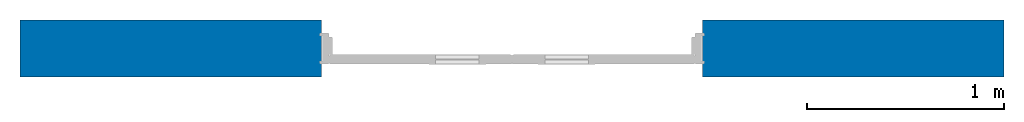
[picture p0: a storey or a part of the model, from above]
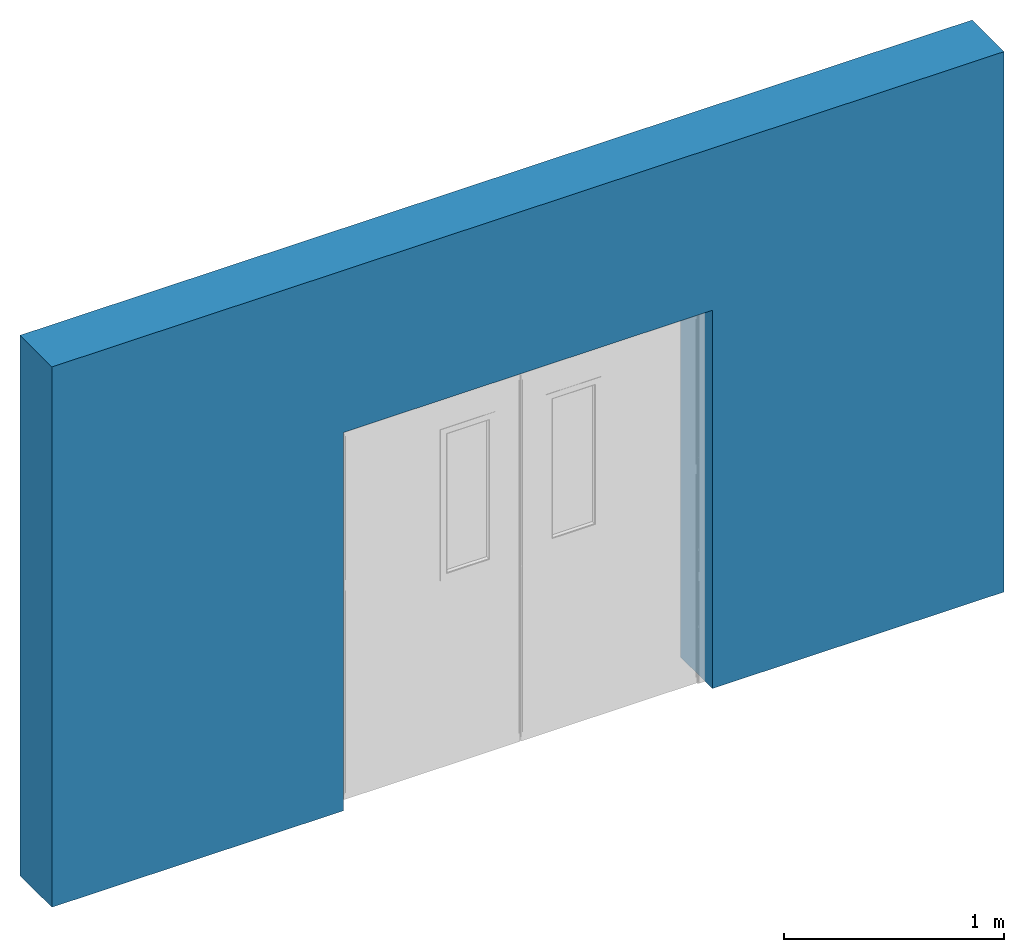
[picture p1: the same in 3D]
Properties of the parts of a building model (IFC2X3)

# File
Description: ViewDefinition [CoordinationView_V2.0]
File name: Project Number
Time: 2016-07-19T09:51:49
Written by: The EXPRESS Data Manager Version 5.01.0100.02.64mod : 6 Jun 2012
Made in: 20131024_2115(x64) - Exporter 3.13.0.0 - Alternate UI 2.13.0.0
Comment: STEP Physical File produced by: The EXPRESS Data Manager Version 5.01.0100.02.64mod : 6 Jun 2012* Module: EDMstepFileFactory/EDMstandAlone* Creation date: Tue Jul 19 09:51:49 2016* Host: ncl-PI11* Database: C:\Users\batyg\AppData\Local\Temp\{1545D58F-4297-423B-B04A-D624175F126E}\ifc* Database version: 5507* Database creation date: Tue Jul 19 09:51:48 2016* Schema: IFC2X3* Model: DataRepository.ifc* Model creation date: Tue Jul 19 09:51:48 2016* Header model: DataRepository.ifc_HeaderModel* Header model creation date: Tue Jul 19 09:51:48 2016* EDMuser: sdai-user* EDMgroup: sdai-group* License ID and type: 5605 : Permanent license. Expiry date: * EDMstepFileFactory options: 020000

# IfcProject, Project Number
LongName: Project Name; Phase: Project Status

# IfcSite, Default
RefLatitude: 51, 30, 0, 549316; RefLongitude: 0, -7, -34, -450321; RefElevation: 0 mm

# IfcBuildingStorey, Level 0
LongName: Level 0; Elevation: 0 mm

# IfcDoor: PostformedDoubleDoorset-VisionPanel11_3Piece_1936x2100mm, NBS_SDSProtectionLtd_CompDrsts_PostformedDoubleDoorset-VisionPanel11:PostformedDoubleDoorset-VisionPanel11_3Piece_1936x2100mm:221256
In: Level 0
Type - OperationType: DOUBLE_DOOR_SINGLE_SWING; ConstructionType: WOOD; ParameterTakesPrecedence: no; Sizeable: no; Material: NBS_Glass_Single, NBS_Concept
Type - NBS_SDSProtectionLtd_CompDrsts_PostformedDoubleDoorset-VisionPanel11:PostformedDoubleDoorset-VisionPanel11_3Piece_1936x2100mm:221256 - PanelOperation: SWINGING
Type - NBS_General - Author: NBS; BIMObjectName: NBS_SDSProtectionLtd_CompositeDoorsets_PostformedDoubleDoorset-VisionPanel11; ManufacturerName: SDS Protection Ltd; ManufacturerURL: www.sdsprotection.co.uk; NBSCertification: http://www.nationalbimlibrary.com/cert/n01kh5x3; NBSDescription: Composite doorsets; NBSNote: n/a; NBSOfficeMasterTag: n/a; NBSReference: 45-25-28/342; NBSTypeID: n/a; ProductInformation: www.sdsprotection.co.uk/doorsets/plastic-encapsulated; Revision: n/a; Uniclass2: 45-60-03/417; Uniclass2015Description: Composite doorsets; Uniclass2015Reference: Pr_30_59_24_16; Uniclass2015Version: Products v1.1; Version: 2
Type - NBS_Data - Accessories: n/a; AcousticPerformanceOptions: Non acoustic rated, 30 dB, 32 dB, 35 dB, 40 dB, 41 dB; AirTransferGrille: no; AirTransferGrilleSize: n/a; AntiFingerTrapRequirement: no; ArchitravesFinishAndColour: n/a; ArchitravesMaterial: n/a; ArchitravesWoodAppearanceClass: n/a; Configuration: Single leaf, single action; DoorFrameColourOptions: Many options available, consult manufacturer's literature; DoorFrameFinishOptions: Fully encapsulated - dFend, Fully encapsulated - Durablend, Fully encapsulated - Hydroclean, Fully encapsulated - Woodgrain, Lacquered, Pre-primed; DoorFrameTypeOptions: Rebated, Split-frame, Traditional; DoorLeafBeadingFixing: n/a; DoorLeafBeadingMaterial: n/a; DoorLeafBeadingType: n/a; DoorLeafCoreOptions: Block, Particle; DoorLeafDoorAccessories: Cappings, Door edge protection, Kickplates; DoorLeafFaceColourOptions: Many options available, consult manufacturer's literature; DoorLeafFaceFinishOptions: dFend, Durablend, Hydroclean; DoorLeafFacingsExternal: 1.5 mm thick thermoplastic; DoorLeafFacingsInternal: 1.5 mm thick thermoplastic; DoorLeafGlazingBeadingOptions: Flushglaze, Overclad; DoorLeafGlazingManifestation: n/a; DoorLeafGlazingSize: 805 x 255 mm (h x w); DoorLeafGlazingTypeOptions: Clear, Frosted, Integral blind, Privacy panel, Smart glass; DoorLeafLippings: n/a; DoorLeafPanelDetails: n/a; DoorLeafPerimeterSeals: n/a; DoorLeafThickness: n/a; ElectronicLock: no; EnvironmentalProductDeclaration: n/a; FireRatingOptions: Non fire rated, FD30, FD60; FloorFinish: n/a; FrameAccessories: n/a; FrameMaterialOptions: Hardwood, Softwood; FramePerimeterSealsOrInserts: n/a; FrameThreshold: n/a; Handing: n/a; Hardware: n/a; HardwareSet: n/a; HeadDetail: n/a; HoldOpen: no; JambDetail: n/a; KeySuiting: n/a; LeafSwing: n/a; OpeningMechanism: no; PerformanceBulletResistance: n/a; PerformanceExplosionResistanceAccessibility: n/a; PerformanceExplosionResistanceBlastDuration: n/a; PerformanceExplosionResistanceOverpressureMaximum: n/a; PerformanceExplosionResistancePressureMode: n/a; PerformanceExplosionResistanceReboundPressureMaximum: n/a; PerformanceRadiation: n/a; PerformanceSmokeControl: n/a; PerformanceStrengthAndDurability: n/a; PerformanceSurfaceSpreadOfFlame: n/a; PreservativeTreatment: n/a; SignageFire: n/a; SignageSecurity: n/a; SignageWayfinding: n/a; ThirdPartyAccreditation: n/a
Type - Pset_DoorCommon - AcousticRating: n/a; FireExit: no; FireRating: n/a; GlazingAreaFraction: 0; HandicapAccessible: no; Infiltration: 0 m3/s; IsExternal: no; Reference: n/a; SecurityRating: n/a; SelfClosing: no; SmokeStop: no; ThermalTransmittance: 0 kg/K/s3
Type - Pset_DoorWindowGlazingType - BeamRadiationTransmittance: 0; FillGas: n/a; GlassColour: n/a; GlassLayers: 1; GlassThickness1: 7 mm; GlassThickness2: 0 mm; GlassThickness3: 0 mm; IsCoated: no; IsLaminated: no; IsTempered: no; IsWired: no; Reflectivity: 0; SolarHeatGainTransmittance: 0; ThermalTransmittanceSummer: 0 kg/K/s3; ThermalTransmittanceWinter: 0 kg/K/s3; Translucency: 0
Type - COBie - AccessibilityPerformance: n/a; AssetType: Fixed; Category: Pr_30_59_24_16:Composite doorsets; CodePerformance: n/a; Color: n/a; Constituents: n/a; Description: Postformed double doorset; DurationUnit: year; ExpectedLife: n/a; Features: n/a; Finish: n/a; Grade: n/a; Manufacturer: www.sdsprotection.co.uk; Material: Wood with thermoplastic cladding; ModelNumber: n/a; ModelReference: Postformed Double Doorset - Vision Panel 11; Name: CompositeDoorsets_PostformedDoubleDoorset-VisionPanel11_SDSProtectionLtd; NominalHeight: 2100 mm; NominalLength: 0 mm; NominalWidth: 1936 mm; ReplacementCost: n/a; Shape: n/a; Size: 1936x2100mm; SustainabilityPerformance: n/a; WarrantyDescription: n/a; WarrantyDurationLabor: n/a; WarrantyDurationParts: n/a; WarrantyDurationUnit: year; WarrantyGuarantorLabor: n/a; WarrantyGuarantorParts: n/a
OverallHeight: 2100 mm; OverallWidth: 1936 mm
NBS_Data - ComponentNumber: n/a; DoorNumber: n/a
COBie - AssetIdentifier: n/a; BarCode: n/a; InstallationDate: 1900-12-31T23:59:59; SerialNumber: n/a; TagNumber: n/a; WarrantyStartDate: 1900-12-31T23:59:59

# IfcWallStandardCase: Basic Wall:Cav - 102 75i 100 p - Lwt, Basic Wall:Cav - 102 75i 100 p - Lwt:217121
In: Level 0
Type - PredefinedType: STANDARD; Material: Brick, Common 102.5 mm, Fiberglass Batt 75 mm, Concrete Masonry Units 100 mm, Gypsum Wall Board 12.5 mm
